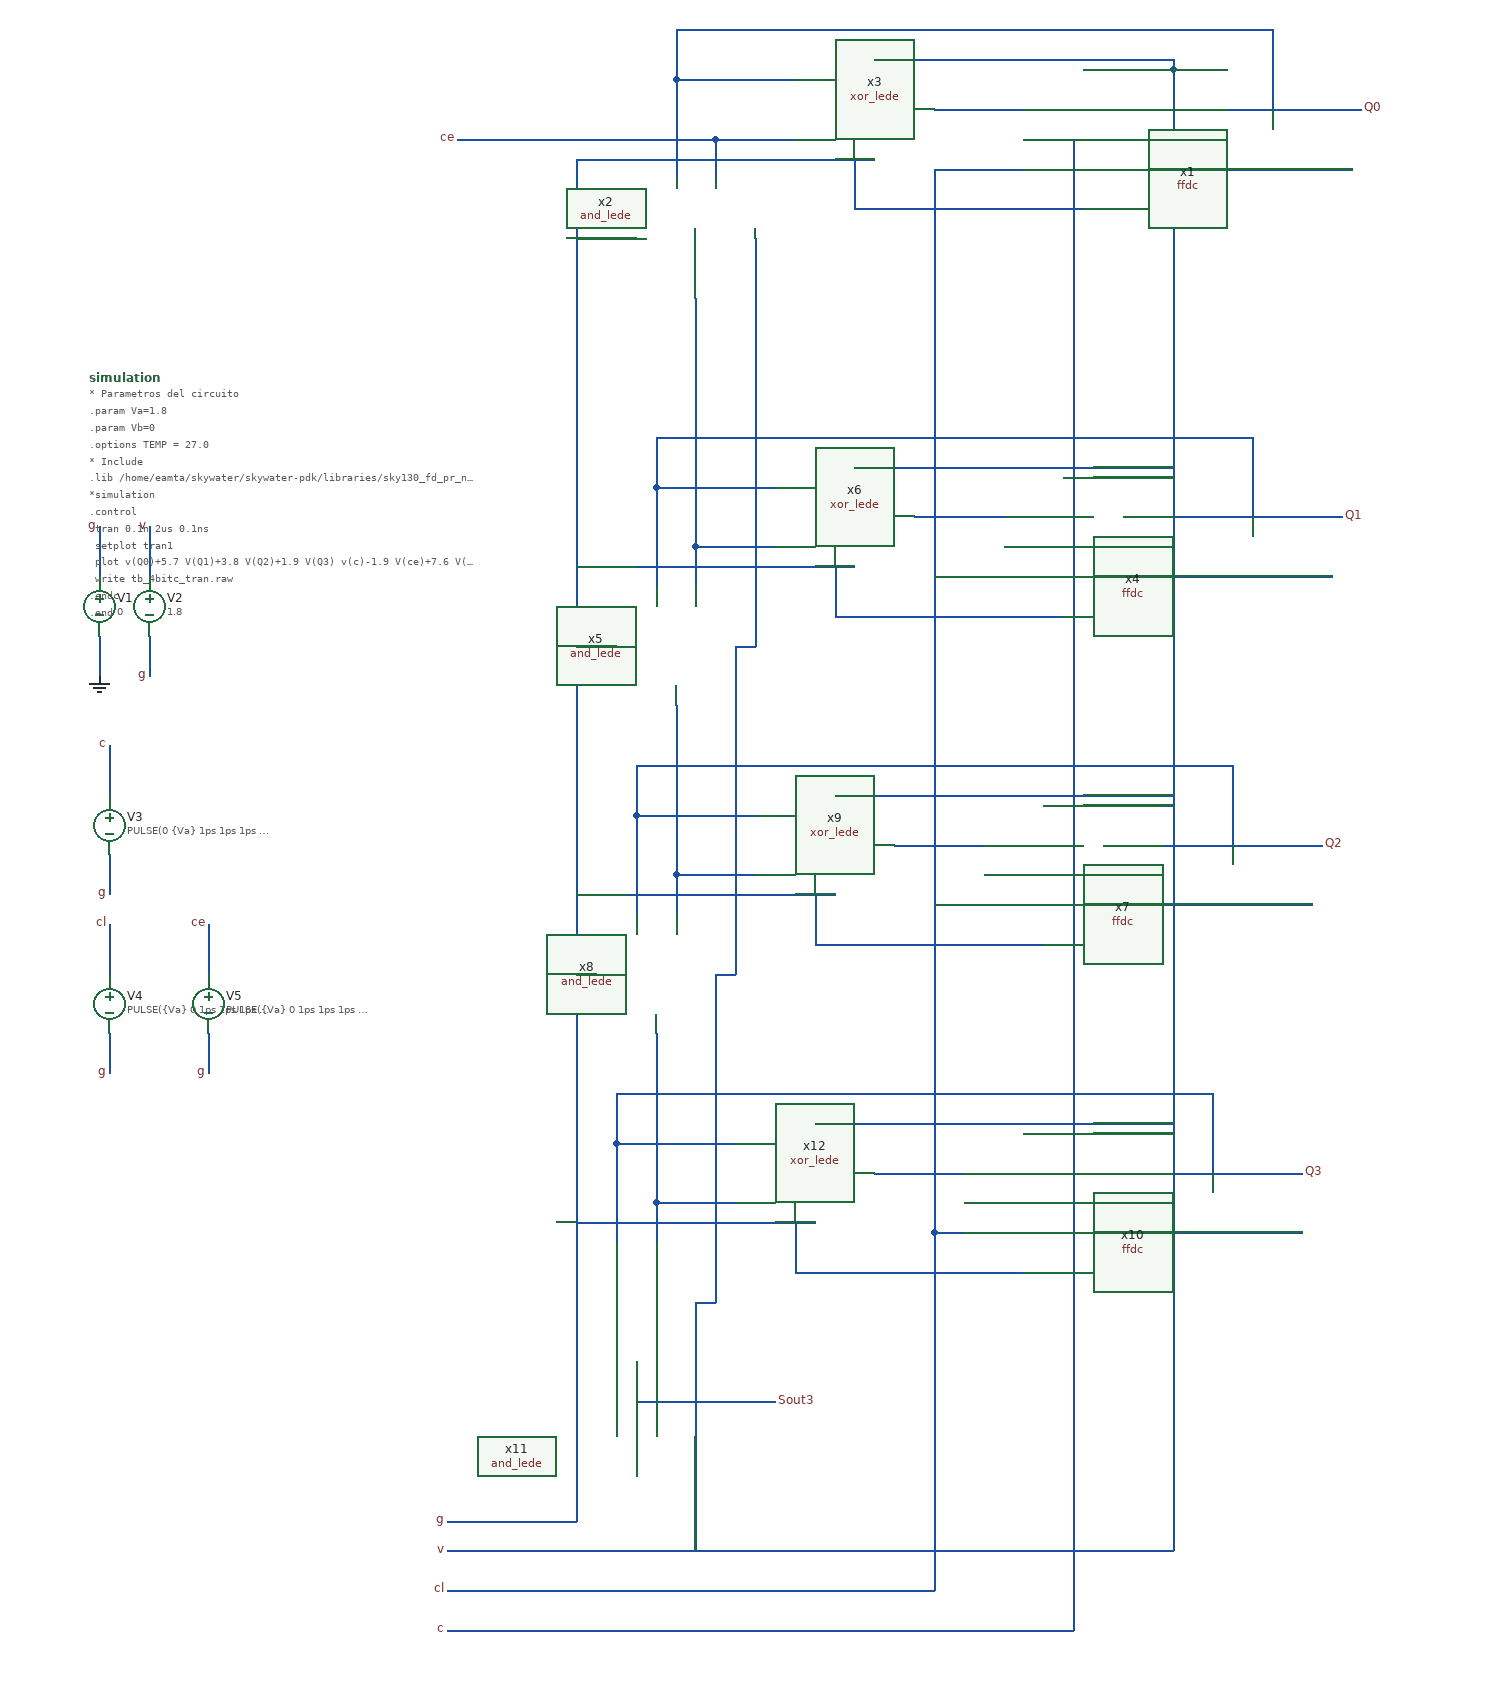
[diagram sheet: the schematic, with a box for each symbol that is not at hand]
v {xschem version=2.9.9 file_version=1.2 }
G {}
K {}
V {}
S {}
E {}
N -810 460 -810 500 { lab=g}
N -810 350 -810 400 { lab=cl}
N -810 170 -810 220 { lab=c}
N -810 280 -810 320 { lab=g}
N -770 -50 -770 0 { lab=v}
N -770 60 -770 100 { lab=g}
N -820 -50 -820 0 { lab=g}
N -820 60 -820 100 { lab=GND}
N 20 -470 110 -470 { lab=#net1}
N -200 -440 -120 -440 { lab=ce}
N -200 -440 -200 -400 { lab=ce}
N -240 -500 -240 -400 { lab=Q0}
N -240 -500 -120 -500 { lab=Q0}
N -240 -550 -240 -500 { lab=Q0}
N -240 -550 260 -550 { lab=Q0}
N -220 -280 -220 -180 { lab=#net2}
N -460 -440 -200 -440 { lab=ce}
N 260 -550 360 -550 { lab=Q0}
N 360 -550 360 -470 { lab=Q0}
N 0 -60 90 -60 { lab=#net3}
N -220 -30 -140 -30 { lab=#net2}
N -220 -30 -220 10 { lab=#net2}
N -260 -90 -260 10 { lab=Q1}
N -260 -90 -140 -90 { lab=Q1}
N -260 -140 -260 -90 { lab=Q1}
N -260 -140 240 -140 { lab=Q1}
N 210 -60 240 -60 { lab=Q1}
N 240 -60 430 -60 { lab=Q1}
N 240 -140 340 -140 { lab=Q1}
N 340 -140 340 -60 { lab=Q1}
N -20 270 70 270 { lab=#net4}
N -240 300 -160 300 { lab=#net5}
N -240 300 -240 340 { lab=#net5}
N -280 240 -280 340 { lab=Q2}
N -280 240 -160 240 { lab=Q2}
N -280 190 -280 240 { lab=Q2}
N -280 190 220 190 { lab=Q2}
N 190 270 220 270 { lab=Q2}
N 220 270 410 270 { lab=Q2}
N 220 190 320 190 { lab=Q2}
N 320 190 320 270 { lab=Q2}
N -40 600 50 600 { lab=#net6}
N -260 630 -180 630 { lab=#net7}
N -260 630 -260 670 { lab=#net7}
N -300 570 -300 670 { lab=Q3}
N -300 570 -180 570 { lab=Q3}
N -300 520 -300 570 { lab=Q3}
N -300 520 200 520 { lab=Q3}
N 170 600 200 600 { lab=Q3}
N 200 600 390 600 { lab=Q3}
N 200 520 300 520 { lab=Q3}
N 300 520 300 600 { lab=Q3}
N -220 -180 -220 -30 { lab=#net2}
N -240 130 -240 300 { lab=#net5}
N -260 460 -260 630 { lab=#net7}
N 170 -510 260 -510 { lab=v}
N 260 -510 260 910 { lab=v}
N 150 -100 260 -100 { lab=v}
N 130 230 260 230 { lab=v}
N 110 560 260 560 { lab=v}
N -100 550 260 550 { lab=v}
N -80 220 260 220 { lab=v}
N -60 -110 260 -110 { lab=v}
N -40 -520 260 -520 { lab=v}
N 260 -520 260 -510 { lab=v}
N 260 910 260 980 { lab=v}
N -470 980 260 980 { lab=v}
N -220 730 -220 980 { lab=v}
N -200 400 -200 730 { lab=v}
N -220 730 -200 730 { lab=v}
N -180 70 -180 400 { lab=v}
N -200 400 -180 400 { lab=v}
N -160 -340 -160 70 { lab=v}
N -180 70 -160 70 { lab=v}
N -340 -420 -340 730 { lab=g}
N -340 -420 -40 -420 { lab=g}
N -60 -370 170 -370 { lab=g}
N -60 -420 -60 -370 { lab=g}
N -340 70 -300 70 { lab=g}
N -340 -10 -60 -10 { lab=g}
N -80 40 150 40 { lab=g}
N -80 -10 -80 40 { lab=g}
N -340 -340 -280 -340 { lab=g}
N -340 320 -80 320 { lab=g}
N -100 370 130 370 { lab=g}
N -100 320 -100 370 { lab=g}
N -340 650 -100 650 { lab=g}
N -340 400 -320 400 { lab=g}
N 40 -410 110 -410 { lab=cl}
N -340 730 -340 950 { lab=g}
N -470 950 -340 950 { lab=g}
N 20 660 50 660 { lab=cl}
N 20 -410 20 660 { lab=cl}
N 20 -410 40 -410 { lab=cl}
N 20 330 70 330 { lab=cl}
N 20 0 90 0 { lab=cl}
N 20 660 20 1020 { lab=cl}
N -470 1020 20 1020 { lab=cl}
N 110 -440 160 -440 { lab=c}
N 160 -440 160 1060 { lab=c}
N 90 -30 160 -30 { lab=c}
N 70 300 160 300 { lab=c}
N 50 630 160 630 { lab=c}
N -470 1060 160 1060 { lab=c}
N -120 700 110 700 { lab=g}
N -120 650 -120 700 { lab=g}
N 230 -470 450 -470 { lab=Q0}
N 230 -410 440 -410 { lab=#net8}
N 210 0 420 0 { lab=#net9}
N 190 330 400 330 { lab=#net10}
N 170 660 390 660 { lab=#net11}
N -280 790 -280 830 { lab=Sout3}
N -280 830 -140 830 { lab=Sout3}
N -710 460 -710 500 { lab=g}
N -710 350 -710 400 { lab=ce}
C {vsource.sym} -820 30 0 0 {name=V1 value=0}
C {vsource.sym} -770 30 0 0 {name=V2 value=1.8}
C {vsource.sym} -810 250 0 0 {name=V3 value="PULSE(0 \{Va\} 1ps 1ps 1ps 20ns 40ns) DC\{Va\}"}
C {vsource.sym} -810 430 0 0 {name=V4 value="PULSE(\{Va\} 0 1ps 1ps 1ps 900ns 1000ns) DC\{Va\}"}
C {gnd.sym} -820 100 0 0 {name=l10 lab=GND}
C {lab_pin.sym} -820 -50 0 0 {name=l11 sig_type=std_logic lab=g}
C {lab_pin.sym} -770 -50 0 0 {name=l12 sig_type=std_logic lab=v}
C {lab_pin.sym} -810 170 0 0 {name=l13 sig_type=std_logic lab=c}
C {lab_pin.sym} -810 350 0 0 {name=l14 sig_type=std_logic lab=cl}
C {lab_pin.sym} -810 500 0 0 {name=l15 sig_type=std_logic lab=g}
C {lab_pin.sym} -810 320 0 0 {name=l16 sig_type=std_logic lab=g}
C {lab_pin.sym} -770 100 0 0 {name=l17 sig_type=std_logic lab=g
}
C {netlist_not_shown.sym} -830 -200 0 0 {name=simulation
only_toplevel=false
value="

* Parametros del circuito
.param Va=1.8
.param Vb=0
.options TEMP = 27.0

* Include
.lib /home/eamta/skywater/skywater-pdk/libraries/sky130_fd_pr_ngspice/latest/models/corners/sky130.lib TT

*simulation
.control
  tran 0.1n 2us 0.1ns
  setplot tran1
  plot v(Q0)+5.7 V(Q1)+3.8 V(Q2)+1.9 V(Q3) v(c)-1.9 V(ce)+7.6 V(cl)+ 9.5
  write tb_4bitc_tran.raw


.endc
.end
"}
C {and_lede.sym} -220 -360 1 0 {name=x2}
C {xor_lede.sym} -110 -470 0 0 {name=x3}
C {and_lede.sym} -240 50 1 0 {name=x5}
C {xor_lede.sym} -130 -60 0 0 {name=x6}
C {and_lede.sym} -260 380 1 0 {name=x8}
C {xor_lede.sym} -150 270 0 0 {name=x9}
C {and_lede.sym} -280 710 1 0 {name=x11}
C {xor_lede.sym} -170 600 0 0 {name=x12}
C {lab_pin.sym} -470 950 0 0 {name=l1 sig_type=std_logic lab=g}
C {lab_pin.sym} -470 980 0 0 {name=l2 sig_type=std_logic lab=v}
C {lab_pin.sym} -470 1020 0 0 {name=l3 sig_type=std_logic lab=cl}
C {lab_pin.sym} -470 1060 0 0 {name=l4 sig_type=std_logic lab=c}
C {lab_pin.sym} -460 -440 0 0 {name=l5 sig_type=std_logic lab=ce}
C {lab_pin.sym} 450 -470 2 0 {name=l6 sig_type=std_logic lab=Q0}
C {lab_pin.sym} 430 -60 2 0 {name=l7 sig_type=std_logic lab=Q1}
C {lab_pin.sym} 410 270 2 0 {name=l8 sig_type=std_logic lab=Q2}
C {lab_pin.sym} 390 600 2 0 {name=l9 sig_type=std_logic lab=Q3}
C {lab_pin.sym} -140 830 2 0 {name=l18 sig_type=std_logic lab=Sout3}
C {vsource.sym} -710 430 0 0 {name=V5 value="PULSE(\{Va\} 0 1ps 1ps 1ps 200ns 1000ns) DC\{Va\}"}
C {lab_pin.sym} -710 350 0 0 {name=l19 sig_type=std_logic lab=ce}
C {lab_pin.sym} -710 500 0 0 {name=l20 sig_type=std_logic lab=g}
C {ffdc.sym} 170 -440 0 0 {name=x1}
C {ffdc.sym} 150 -30 0 0 {name=x4}
C {ffdc.sym} 130 300 0 0 {name=x7}
C {ffdc.sym} 110 630 0 0 {name=x10}
